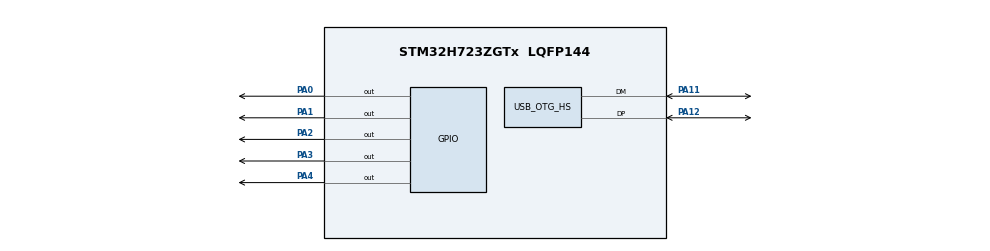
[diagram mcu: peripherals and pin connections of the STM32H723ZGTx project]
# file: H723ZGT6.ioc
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CORTEX_M7.default_mode_Activation=1
Dma.Request0=TIM2_UP
Dma.TIM2_UP.0.Direction=DMA_MEMORY_TO_PERIPH
Dma.TIM2_UP.0.EventEnable=DISABLE
Dma.TIM2_UP.0.FIFOMode=DMA_FIFOMODE_DISABLE
Dma.TIM2_UP.0.Instance=DMA1_Stream0
Dma.TIM2_UP.0.MemDataAlignment=DMA_MDATAALIGN_WORD
Dma.TIM2_UP.0.MemInc=DMA_MINC_ENABLE
Dma.TIM2_UP.0.Mode=DMA_CIRCULAR
Dma.TIM2_UP.0.PeriphDataAlignment=DMA_PDATAALIGN_WORD
Dma.TIM2_UP.0.PeriphInc=DMA_PINC_DISABLE
Dma.TIM2_UP.0.Polarity=HAL_DMAMUX_REQ_GEN_RISING
Dma.TIM2_UP.0.Priority=DMA_PRIORITY_LOW
Dma.TIM2_UP.0.RequestNumber=1
Dma.TIM2_UP.0.SignalID=NONE
Dma.TIM2_UP.0.SyncEnable=DISABLE
Dma.TIM2_UP.0.SyncPolarity=HAL_DMAMUX_SYNC_NO_EVENT
Dma.TIM2_UP.0.SyncRequestNumber=1
Dma.TIM2_UP.0.SyncSignalID=NONE
Mcu.Family=STM32H7
Mcu.Name=STM32H723ZGTx
Mcu.Package=LQFP144
NVIC.DMA1_Stream0_IRQn=true\:0\:0\:false\:false\:true\:false\:true\:true
NVIC.OTG_HS_IRQn=true\:0\:0\:false\:false\:true\:false\:true\:true
NVIC.PriorityGroup=NVIC_PRIORITYGROUP_4
PA0.Signal=GPIO_Output
PA1.Signal=GPIO_Output
PA11.Mode=Device_Only_FS
PA11.Signal=USB_OTG_HS_DM
PA12.Mode=Device_Only_FS
PA12.Signal=USB_OTG_HS_DP
PA2.Signal=GPIO_Output
PA3.Signal=GPIO_Output
PA4.Signal=GPIO_Output
PC14-OSC32_IN.Mode=LSE-External-Oscillator
PC14-OSC32_IN.Signal=RCC_OSC32_IN
PC15-OSC32_OUT.Mode=LSE-External-Oscillator
PC15-OSC32_OUT.Signal=RCC_OSC32_OUT
PH0-OSC_IN.Mode=HSE-External-Oscillator
PH0-OSC_IN.Signal=RCC_OSC_IN
PH1-OSC_OUT.Mode=HSE-External-Oscillator
PH1-OSC_OUT.Signal=RCC_OSC_OUT
ProjectManager.HeapSize=0x200
ProjectManager.StackSize=0x400
ProjectManager.TargetToolchain=STM32CubeIDE
RCC.ADCFreq_Value=50390625
RCC.APB1Freq_Value=96000671.38671875
RCC.APB2Freq_Value=96000671.38671875
RCC.APB3Freq_Value=96000671.38671875
RCC.APB4Freq_Value=96000671.38671875
RCC.CortexFreq_Value=192001342.7734375
RCC.D1PPRE=RCC_APB3_DIV2
RCC.D2PPRE1=RCC_APB1_DIV2
RCC.D2PPRE2=RCC_APB2_DIV2
RCC.D3PPRE=RCC_APB4_DIV2
RCC.DIVM1=2
RCC.DIVN1=15
RCC.DIVP1=1
RCC.HCLKFreq_Value=192001342.7734375
RCC.PLLFRACN=2950
RCC.PLLSourceVirtual=RCC_PLLSOURCE_HSE
RCC.SYSCLKFreq_VALUE=192001342.7734375
RCC.SYSCLKSource=RCC_SYSCLKSOURCE_PLLCLK
RCC.USBFreq_Value=96000671.38671875
USB_DEVICE.CLASS_NAME_HS=CDC
USB_DEVICE.VirtualMode=Cdc
USB_DEVICE.VirtualModeHS=Cdc_HS
USB_OTG_HS.VirtualMode-Device_Only_FS=Device_Only_FS
VP_MEMORYMAP_VS_MEMORYMAP.Mode=CurAppReg
VP_TIM2_VS_ClockSourceINT.Mode=Internal
VP_USB_DEVICE_VS_USB_DEVICE_CDC_HS.Mode=CDC_HS
board=custom

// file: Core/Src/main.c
/* USER CODE BEGIN Header */
/**
  ******************************************************************************
  * @file           : main.c
  * @brief          : TIM2+DMA waveform generator with USB CDC protocol.
  *                   Clock: HSI 64 MHz + HSI48 for USB.
  ******************************************************************************
  */
/* USER CODE END Header */

#include "stm32h7xx_hal.h"
#include "usb_device.h"
#include "app_protocol.h"
#include "app_wavegen.h"
#include "app_spi.h"
#include "app_adc.h"
#include "app_dac.h"
#include <string.h>

/* Provide symbols required by other .c files still in the build */
TIM_HandleTypeDef htim2;
DMA_HandleTypeDef hdma_tim2_up;

void Error_Handler(void)
{
    while (1) { }
}

/* Private function prototypes */
static void SystemClock_Config(void);
static void MX_GPIO_Init(void);
static void MX_DMA_Init(void);
static void MX_TIM2_Init(void);

/* Protocol callback forward declaration */
static void OnFrameReceived(const Frame_t *frame);

int main(void)
{
    /* MCU Configuration--------------------------------------------------------*/
    HAL_Init();
    SystemClock_Config();

    /* Initialize all configured peripherals */
    MX_GPIO_Init();
    MX_DMA_Init();
    MX_TIM2_Init();

    /* USER CODE BEGIN 2 */
    /* Init waveform generator, SPI, ADC and protocol stack */
    APP_WaveGen_Init();
    APP_SPI_Init();
    APP_ADC_Init();
    APP_DAC_Init();
    APP_Protocol_Init(OnFrameReceived);

    /* Start USB CDC device */
    MX_USB_DEVICE_Init();

    /* Default waveform: 1 kHz square wave on SCLK (PA1), 下降沿触发 */
    /* 周期 = 2 个Update: 先高电平(SET), 再低电平(RESET), 下降沿有效 */
    /* Configure TIM2 for 2 kHz update rate @ 192 MHz timer clock (APB1=96MHz, timer=192MHz) */
    __HAL_TIM_SET_PRESCALER(&htim2, 0);
    __HAL_TIM_SET_AUTORELOAD(&htim2, 95999);   /* 192 MHz / 96000 = 2 kHz */
    HAL_TIM_GenerateEvent(&htim2, TIM_EVENTSOURCE_UPDATE);

    static uint32_t s_defaultWave[2];
    s_defaultWave[0] = (1u << 1);   /* SET  PA1/SCLK -> 高电平 */
    s_defaultWave[1] = (1u << 17);  /* RESET PA1/SCLK -> 低电平 (下降沿) */

    HAL_DMA_Start(&hdma_tim2_up,
                  (uint32_t)s_defaultWave,
                  (uint32_t)&GPIOA->BSRR,
                  2);
    __HAL_TIM_ENABLE_DMA(&htim2, TIM_DMA_UPDATE);
    HAL_TIM_Base_Start(&htim2);
    /* USER CODE END 2 */

    /* Infinite loop */
    uint32_t tickLast = HAL_GetTick();
    uint32_t tickTest = HAL_GetTick();
    while (1)
    {
        APP_ADC_Poll();
        /* Process received USB frames in main-loop context (not in ISR) */
        Frame_t rxFrame;
        while (APP_Protocol_GetPendingFrame(&rxFrame)) {
            OnFrameReceived(&rxFrame);
        }

        /* USB uplink heartbeat: send test frame every 1s */
        if (HAL_GetTick() - tickTest >= 1000) {
            static Frame_t testFrame;
            testFrame.cmd = 0xFF;
            testFrame.len = 4;
            memcpy(testFrame.payload, "TEST", 4);
            APP_Protocol_SendFrame(&testFrame);
            tickTest = HAL_GetTick();
        }

        /* Heartbeat on PG7: 1 Hz slow blink (non-blocking) */
        if (HAL_GetTick() - tickLast >= 500) {
            HAL_GPIO_TogglePin(GPIOG, GPIO_PIN_7);
            tickLast = HAL_GetTick();
        }
    }
}

/**
  * @brief  Protocol frame callback — handles commands from host PC.
  */
static void OnFrameReceived(const Frame_t *frame)
{
    if (frame == NULL) return;

    switch (frame->cmd)
    {
        case CMD_WAVE_CONFIG:
        {
            /* Payload: sample_rate_hz (4B) + num_points (2B) + ch_mask (1B) */
            if (frame->len < 7) {
                APP_Protocol_SendAck(CMD_WAVE_CONFIG, false);
                break;
            }
            WaveConfig_t cfg = {0};
            cfg.sample_rate_hz = ((uint32_t)frame->payload[0])
                               | ((uint32_t)frame->payload[1] << 8)
                               | ((uint32_t)frame->payload[2] << 16)
                               | ((uint32_t)frame->payload[3] << 24);
            cfg.num_points = ((uint16_t)frame->payload[4])
                           | ((uint16_t)frame->payload[5] << 8);
            cfg.ch_mask = frame->payload[6];

            bool ok = APP_WaveGen_Configure(&cfg);
            APP_Protocol_SendAck(CMD_WAVE_CONFIG, ok);
            break;
        }

        case CMD_WAVE_DATA:
        {
            /* Payload: array of 32-bit BSRR masks */
            if (frame->len == 0 || (frame->len % 4) != 0) {
                APP_Protocol_SendAck(CMD_WAVE_DATA, false);
                break;
            }
            uint16_t num_words = frame->len / 4;
            uint32_t data[256];
            if (num_words > 256) num_words = 256;
            for (uint16_t i = 0; i < num_words; i++) {
                data[i] = ((uint32_t)frame->payload[i*4])
                        | ((uint32_t)frame->payload[i*4 + 1] << 8)
                        | ((uint32_t)frame->payload[i*4 + 2] << 16)
                        | ((uint32_t)frame->payload[i*4 + 3] << 24);
            }
            bool ok = APP_WaveGen_LoadData(data, num_words);
            APP_Protocol_SendAck(CMD_WAVE_DATA, ok);
            break;
        }

        case CMD_WAVE_CTRL:
        {
            /* Payload[0]: 1 = start, 0 = stop */
            if (frame->len < 1) {
                APP_Protocol_SendAck(CMD_WAVE_CTRL, false);
                break;
            }
            bool ok;
            if (frame->payload[0]) {
                ok = APP_WaveGen_Start();
            } else {
                APP_WaveGen_Stop();
                ok = true;
            }
            APP_Protocol_SendAck(CMD_WAVE_CTRL, ok);
            break;
        }

        case CMD_SPI_CONFIG:
        {
            /* Payload: [cpol_cpha_byte, prescaler, data_size] */
            if (frame->len < 3) {
                APP_Protocol_SendAck(CMD_SPI_CONFIG, false);
                break;
            }
            SpiConfig_t cfg = {0};
            cfg.cpol = (frame->payload[0] >> 1) & 1;
            cfg.cpha = frame->payload[0] & 1;
            cfg.prescaler = frame->payload[1];
            cfg.data_size = frame->payload[2];
            bool ok = APP_SPI_Configure(&cfg);
            APP_Protocol_SendAck(CMD_SPI_CONFIG, ok);
            break;
        }

        case CMD_SPI_XFER:
        {
            /* Batch register write format:
             * payload[0] = num_regs
             * payload[1] = data_width (8 or 16)
             * payload[2..] = addr, data, addr, data ...
             */
            if (frame->len < 2) {
                APP_Protocol_SendAck(CMD_SPI_XFER, false);
                break;
            }
            uint8_t num_regs = frame->payload[0];
            uint8_t data_width = frame->payload[1];
            bool ok = APP_SPI_WriteRegs(&frame->payload[2], num_regs, data_width);
            APP_Protocol_SendAck(CMD_SPI_XFER, ok);
            break;
        }

        case CMD_ADC_CONFIG:
        {
            /* Payload: ch_mask(1B) + sample_rate_hz(4B LE) + mode(1B) */
            if (frame->len < 6) {
                APP_Protocol_SendAck(CMD_ADC_CONFIG, false);
                break;
            }
            AdcConfig_t cfg = {0};
            cfg.ch_mask = frame->payload[0];
            cfg.sample_rate_hz = ((uint32_t)frame->payload[1])
                               | ((uint32_t)frame->payload[2] << 8)
                               | ((uint32_t)frame->payload[3] << 16)
                               | ((uint32_t)frame->payload[4] << 24);
            cfg.mode = frame->payload[5];
            bool ok = APP_ADC_Configure(&cfg);
            APP_Protocol_SendAck(CMD_ADC_CONFIG, ok);
            break;
        }

        case CMD_ADC_CTRL:
        {
            /* Payload[0]: 1 = start, 0 = stop */
            if (frame->len < 1) {
                APP_Protocol_SendAck(CMD_ADC_CTRL, false);
                break;
            }
            bool ok;
            if (frame->payload[0]) {
                ok = APP_ADC_Start();
            } else {
                APP_ADC_Stop();
                ok = true;
            }
            APP_Protocol_SendAck(CMD_ADC_CTRL, ok);
            break;
        }

        case CMD_DAC_SET:
        {
            /* Payload: value(2B LE, 12-bit) */
            if (frame->len < 2) {
                APP_Protocol_SendAck(CMD_DAC_SET, false);
                break;
            }
            uint16_t value = ((uint16_t)frame->payload[0])
                           | ((uint16_t)frame->payload[1] << 8);
            bool ok = APP_DAC_SetValue(value);
            APP_Protocol_SendAck(CMD_DAC_SET, ok);
            break;
        }

        default:
            /* Unknown command — send NACK */
            APP_Protocol_SendAck(frame->cmd, false);
            break;
    }
}

static void SystemClock_Config(void)
{
    RCC_OscInitTypeDef RCC_OscInitStruct = {0};
    RCC_ClkInitTypeDef RCC_ClkInitStruct = {0};

    /* Enable HSI48 for USB clock source */
    __HAL_RCC_HSI48_ENABLE();
    while (__HAL_RCC_GET_FLAG(RCC_FLAG_HSI48RDY) == RESET) { }

    /* Scale voltage regulator for 192 MHz */
    if (HAL_PWREx_ControlVoltageScaling(PWR_REGULATOR_VOLTAGE_SCALE0) != HAL_OK)
    {
        Error_Handler();
    }

    /* Configure main PLL: HSI 64 MHz -> PLL1 -> 192 MHz
     * M=4, N=24, P=2  => 64/4*24/2 = 192 MHz
     */
    RCC_OscInitStruct.OscillatorType = RCC_OSCILLATORTYPE_HSI;
    RCC_OscInitStruct.HSIState = RCC_HSI_ON;
    RCC_OscInitStruct.HSICalibrationValue = RCC_HSICALIBRATION_DEFAULT;
    RCC_OscInitStruct.PLL.PLLState = RCC_PLL_ON;
    RCC_OscInitStruct.PLL.PLLSource = RCC_PLLSOURCE_HSI;
    RCC_OscInitStruct.PLL.PLLM = 4;
    RCC_OscInitStruct.PLL.PLLN = 24;
    RCC_OscInitStruct.PLL.PLLP = 2;
    RCC_OscInitStruct.PLL.PLLQ = 4;
    RCC_OscInitStruct.PLL.PLLR = 2;
    RCC_OscInitStruct.PLL.PLLRGE = RCC_PLL1VCIRANGE_3;
    RCC_OscInitStruct.PLL.PLLVCOSEL = RCC_PLL1VCOWIDE;
    RCC_OscInitStruct.PLL.PLLFRACN = 0;
    if (HAL_RCC_OscConfig(&RCC_OscInitStruct) != HAL_OK)
    {
        Error_Handler();
    }

    RCC_ClkInitStruct.ClockType = RCC_CLOCKTYPE_HCLK|RCC_CLOCKTYPE_SYSCLK
                                |RCC_CLOCKTYPE_PCLK1|RCC_CLOCKTYPE_PCLK2
                                |RCC_CLOCKTYPE_D3PCLK1|RCC_CLOCKTYPE_D1PCLK1;
    RCC_ClkInitStruct.SYSCLKSource = RCC_SYSCLKSOURCE_PLLCLK;
    RCC_ClkInitStruct.SYSCLKDivider = RCC_SYSCLK_DIV1;
    RCC_ClkInitStruct.AHBCLKDivider = RCC_HCLK_DIV1;
    RCC_ClkInitStruct.APB3CLKDivider = RCC_APB3_DIV2;
    RCC_ClkInitStruct.APB1CLKDivider = RCC_APB1_DIV2;
    RCC_ClkInitStruct.APB2CLKDivider = RCC_APB2_DIV2;
    RCC_ClkInitStruct.APB4CLKDivider = RCC_APB4_DIV2;

    /* FLASH_LATENCY_4 for 192 MHz @ 3.3V */
    if (HAL_RCC_ClockConfig(&RCC_ClkInitStruct, FLASH_LATENCY_4) != HAL_OK)
    {
        Error_Handler();
    }
}

static void MX_TIM2_Init(void)
{
    TIM_ClockConfigTypeDef sClockSourceConfig = {0};
    TIM_MasterConfigTypeDef sMasterConfig = {0};

    htim2.Instance = TIM2;
    htim2.Init.Prescaler = 0;
    htim2.Init.CounterMode = TIM_COUNTERMODE_UP;
    htim2.Init.Period = 4294967295;
    htim2.Init.ClockDivision = TIM_CLOCKDIVISION_DIV1;
    htim2.Init.AutoReloadPreload = TIM_AUTORELOAD_PRELOAD_DISABLE;
    if (HAL_TIM_Base_Init(&htim2) != HAL_OK)
    {
        Error_Handler();
    }
    sClockSourceConfig.ClockSource = TIM_CLOCKSOURCE_INTERNAL;
    if (HAL_TIM_ConfigClockSource(&htim2, &sClockSourceConfig) != HAL_OK)
    {
        Error_Handler();
    }
    sMasterConfig.MasterOutputTrigger = TIM_TRGO_RESET;
    sMasterConfig.MasterSlaveMode = TIM_MASTERSLAVEMODE_DISABLE;
    if (HAL_TIMEx_MasterConfigSynchronization(&htim2, &sMasterConfig) != HAL_OK)
    {
        Error_Handler();
    }
}

static void MX_DMA_Init(void)
{
    __HAL_RCC_DMA1_CLK_ENABLE();
    /* H723 DMAMUX1 shares DMA1 clock (no separate RCC bit) */
    HAL_NVIC_SetPriority(DMA1_Stream0_IRQn, 0, 0);
    HAL_NVIC_EnableIRQ(DMA1_Stream0_IRQn);
}

static void MX_GPIO_Init(void)
{
    GPIO_InitTypeDef GPIO_InitStruct = {0};

    __HAL_RCC_GPIOC_CLK_ENABLE();
    __HAL_RCC_GPIOH_CLK_ENABLE();
    __HAL_RCC_GPIOA_CLK_ENABLE();
    __HAL_RCC_GPIOB_CLK_ENABLE();

    HAL_GPIO_WritePin(GPIOA, GPIO_PIN_0|GPIO_PIN_1|GPIO_PIN_2|GPIO_PIN_3, GPIO_PIN_RESET);

    /* ADC pins: PA6, PA7, PB0, PB1, PC0, PC1, PC2, PC3 as analog */
    GPIO_InitTypeDef GPIO_InitStructAnalog = {0};
    GPIO_InitStructAnalog.Mode = GPIO_MODE_ANALOG;
    GPIO_InitStructAnalog.Pull = GPIO_NOPULL;

    GPIO_InitStructAnalog.Pin = GPIO_PIN_4 | GPIO_PIN_6 | GPIO_PIN_7;
    HAL_GPIO_Init(GPIOA, &GPIO_InitStructAnalog);

    GPIO_InitStructAnalog.Pin = GPIO_PIN_0 | GPIO_PIN_1;
    HAL_GPIO_Init(GPIOB, &GPIO_InitStructAnalog);

    GPIO_InitStructAnalog.Pin = GPIO_PIN_0 | GPIO_PIN_1 | GPIO_PIN_2 | GPIO_PIN_3;
    HAL_GPIO_Init(GPIOC, &GPIO_InitStructAnalog);

    __HAL_RCC_SYSCFG_CLK_ENABLE();

    GPIO_InitStruct.Pin = GPIO_PIN_0|GPIO_PIN_1|GPIO_PIN_2|GPIO_PIN_3;
    GPIO_InitStruct.Mode = GPIO_MODE_OUTPUT_PP;
    GPIO_InitStruct.Pull = GPIO_NOPULL;
    GPIO_InitStruct.Speed = GPIO_SPEED_FREQ_VERY_HIGH;
    HAL_GPIO_Init(GPIOA, &GPIO_InitStruct);

    HAL_GPIO_WritePin(GPIOA, GPIO_PIN_5, GPIO_PIN_RESET);
    GPIO_InitStruct.Pin = GPIO_PIN_5;
    GPIO_InitStruct.Mode = GPIO_MODE_OUTPUT_PP;
    GPIO_InitStruct.Pull = GPIO_NOPULL;
    GPIO_InitStruct.Speed = GPIO_SPEED_FREQ_VERY_HIGH;
    HAL_GPIO_Init(GPIOA, &GPIO_InitStruct);

    /* PG7 on-board LED */
    __HAL_RCC_GPIOG_CLK_ENABLE();
    GPIO_InitStruct.Pin = GPIO_PIN_7;
    GPIO_InitStruct.Mode = GPIO_MODE_OUTPUT_PP;
    GPIO_InitStruct.Pull = GPIO_NOPULL;
    GPIO_InitStruct.Speed = GPIO_SPEED_FREQ_LOW;
    HAL_GPIO_Init(GPIOG, &GPIO_InitStruct);
    HAL_GPIO_WritePin(GPIOG, GPIO_PIN_7, GPIO_PIN_SET);
}
